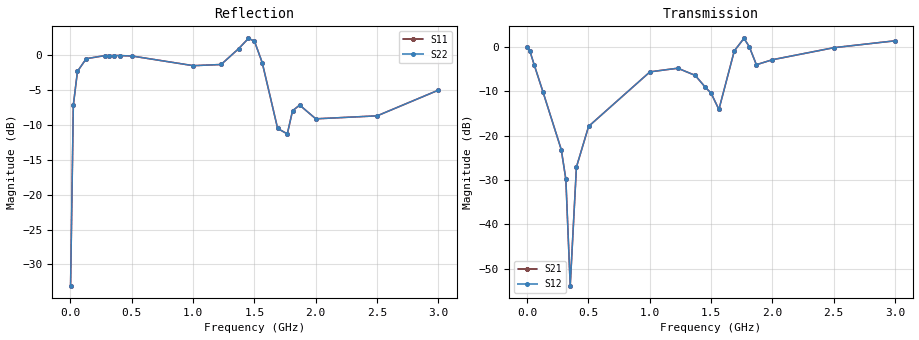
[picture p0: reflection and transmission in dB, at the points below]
!s-Parameter Generated by FASTRON Sdn. Bhd.
!FASTRON P/N : MICC-R39X
!Keysight Technologies,E4991B,MY54100416,A.01.15
!Date: Fri Aug 21 14:01:06 2026
!Version  : Rev00 Fri Aug 21 14:01:06 2026
!Data & Calibration Information:
!PortZ  Port1:50+j0  Port2:50+j0
!When reading, reference impedance value at option line is always used.
! Remarks : This data is being provided solely for informational purposes.
!Freq	S11	S21	S12	S22
# Hz S dB R 50
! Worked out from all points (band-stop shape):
!   1601 points, 1 MHz to 3 GHz, reference 50 ohm
!   highest |S21| = 1.91 dB at 1.769 GHz (marker M1); lowest = -53.8 dB at 351.5 MHz (marker M2)
!   |S21| within 3 dB of the highest: 1.687 GHz to 1.827 GHz (139.8 MHz wide, 7.96 % of centre); 2.294 GHz to end of sweep (the widest 2 of 3)
!   lowest |S11| = -33.1 dB at 1 MHz (marker M3), VSWR 1.05, Z = 50.2 + j2.22 ohm
!   |S11| at or under -10 dB: start of sweep to 15.94 MHz; 1.685 GHz to 1.784 GHz (99.57 MHz wide, 5.74 % of centre)
!   |S22| runs from -33.1 to 2.5 dB; largest |S21 - S12| = 0
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1000000  -33.06 84.1  -0.02 -1.3  -0.02 -1.3  -33.06 84.1
2.34925e7  -7.14 62.7  -1.02 -26.1  -1.02 -26.1  -7.14 62.7
5.723125e7  -2.30 39.0  -4.01 -50.1  -4.01 -50.1  -2.30 39.0
1.284575e8  -0.48 18.3  -10.07 -71.1  -10.07 -71.1  -0.48 18.3
2.784075e8  -0.04 4.0  -23.14 -84.4  -23.14 -84.4  -0.04 4.0
3.15895e8  -0.02 1.8  -29.83 -84.6  -29.83 -84.6  -0.02 1.8
3.515081e8  -0.02 -0.0  -53.79 18.0  -53.79 18.0  -0.02 -0.0
4.021162e8  -0.03 -2.5  -27.08 84.9  -27.08 84.9  -0.03 -2.5
5.014581e8  -0.09 -7.3  -17.91 81.5  -17.91 81.5  -0.09 -7.3
1.001916e9  -1.48 -31.5  -5.63 57.5  -5.63 57.5  -1.48 -31.5
1.228716e9  -1.31 -35.0  -4.81 59.1  -4.81 59.1  -1.31 -35.0
1.371168e9  0.95 -25.3  -6.43 91.0  -6.43 91.0  0.95 -25.3
1.451766e9  2.44 -6.9  -9.05 153.1  -9.05 153.1  2.44 -6.9
1.5005e9  2.04 7.2  -10.44 -148.0  -10.44 -148.0  2.04 7.2
1.564229e9  -1.05 9.8  -14.10 -49.9  -14.10 -49.9  -1.05 9.8
1.689812e9  -10.49 -62.2  -0.91 17.1  -0.91 17.1  -10.49 -62.2
1.768536e9  -11.27 150.6  1.91 -6.2  1.91 -6.2  -11.27 150.6
1.811646e9  -7.94 79.4  0.06 -23.0  0.06 -23.0  -7.94 79.4
1.869752e9  -7.14 25.0  -4.02 -17.1  -4.02 -17.1  -7.14 25.0
2.000958e9  -9.11 -29.5  -2.90 13.9  -2.90 13.9  -9.11 -29.5
2.501416e9  -8.68 -76.0  -0.19 21.4  -0.19 21.4  -8.68 -76.0
3e9  -5.00 -92.7  1.36 28.7  1.36 28.7  -5.00 -92.7
